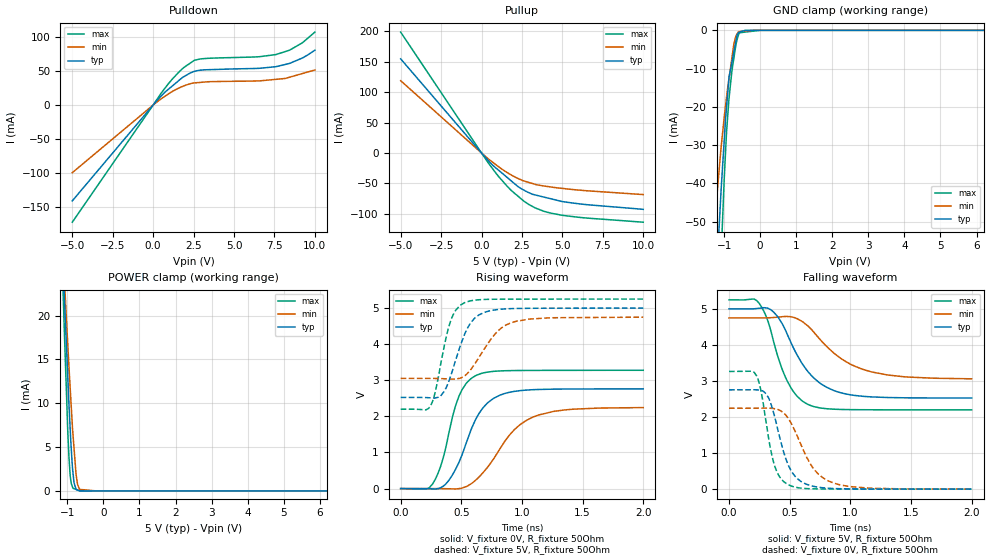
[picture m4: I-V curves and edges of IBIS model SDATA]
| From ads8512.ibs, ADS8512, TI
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|   sdata Model
[Model]   SDATA
Model_type   3-state
Polarity   Non-Inverting
Vmeas = 2.5
Vref = 2.5
Cref = 10pF
Rref = 50
|   typ   min   max
|   (nom PVT)   (Fast PVT)   (slow PVT)
|C_comp from frequency method(29MHz)
|C_comp   3.620e-12   4.211e-12   3.057e-12
|ON state : BUFFER OUTPUT TURNED HIGH
|C_comp   3.711e-12   3.139e-12   4.318e-12
|OFF state: BUFFER IN HIGH IMPEDANCE
|C_comp   3.252e-12   3.813e-12   2.654e-12
|C_comp from LC tank measurement(L=1nH)
|Resonant Frequency(Hz)   2.990e+09   3.140e+09   2.900e+09
C_comp   2.836e-12   2.572e-12   3.015e-12
|ON state : BUFFER OUTPUT TURNED HIGH
|Resonant Frequency(Hz)   2.990e+09   3.140e+09   2.900e+09
|C_comp   2.836e-12   2.572e-12   3.015e-12
|OFF state: BUFFER IN HIGH IMPEDANCE
|Resonant Frequency(Hz)   3.150e+09   3.390e+09   2.990e+09
|C_comp   2.555e-12   2.206e-12   2.836e-12
| Where nom  PVT is Nominal Process,  5V,  25C
|   Fast PVT is Strong Process,   5.25V,  -40C
|   Slow PVT is Weak Process,   4.75V,  85C
[Voltage Range]   5   4.75   5.25
|Ambient Temperature   25   85   -40
|Junction Temperature
[Temperature Range]   25   85   -40
[Pullup Reference]   5   4.75   5.25
[Pulldown Reference]   0   0   0
[Power Clamp Reference]   5   4.75   5.25
[GND Clamp Reference]   0   0   0
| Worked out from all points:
|   slope of the pulldown table from 0 to 0.75 V, typ, clamps not added: 38.6 ohm
|   slope of the pullup table from 0 to 0.75 V, typ, clamps not added: 34.9 ohm
|   GND clamp passes 1 mA (typ) near -0.63 V on its own axis
|   POWER clamp passes 1 mA (typ) near -0.82 V on its own axis
|   falling waveform, V_fixture 5V, R_fixture 50Ohm: 20-80 % time 269ps typ, 361ps min, 188ps max; typ from 5 V to 2.53 V
|   rising waveform, V_fixture 0V, R_fixture 50Ohm: 20-80 % time 217ps typ, 314ps min, 156ps max; typ from 0 V to 2.76 V
|   rising waveform, V_fixture 5V, R_fixture 50Ohm: 20-80 % time 159ps typ, 219ps min, 118ps max; typ from 2.52 V to 5 V
|   falling waveform, V_fixture 0V, R_fixture 50Ohm: 20-80 % time 146ps typ, 209ps min, 106ps max; typ from 2.76 V to 0.004 V
[Pulldown]
|   Voltage   I(typ)   I(min)   I(max)
-5V       -141.2mA   -99.65mA   -172.6mA
255mV     7.087mA    4.92mA     8.994mA
700mV     18.42mA    12.51mA    23.9mA
1.145V    27.31mA    19.44mA    37.2mA
1.906V    41.92mA    28.28mA    55.49mA
2.551V    49.63mA    32.64mA    66mA
2.94V     51.44mA    33.43mA    68.06mA
6.557V    54.15mA    35.59mA    71.22mA
7.591V    56.54mA    37.88mA    74.4mA
8.442V    61.44mA    41.08mA    80.94mA
9.229V    69.37mA    46.44mA    91.74mA
10V       80.82mA    51.68mA    107.5mA
[GND Clamp]
|   Voltage   I(typ)   I(min)   I(max)
-5V       -873.3mA   -631.6mA   -1.21A
-1.306V   -81.05mA   -54.86mA   -119.8mA
-1.176V   -58.06mA   -40.62mA   -83.69mA
-1.093V   -43.33mA   -31.5mA    -61.76mA
-1.071V   -39.84mA   -29.49mA   -56.18mA
-997.5mV  -28.82mA   -22.72mA   -38.9mA
-934.5mV  -20.28mA   -17.65mA   -27.02mA
-866.2mV  -12.47mA   -12.74mA   -17.97mA
-726.8mV  -5.5mA     -3.506mA   -7.118mA
-598.5mV  -597.9uA   -334.5uA   -1.123mA
0V        0A         0A         0A
10V       0A         0A         0A
[Pullup]
|   Voltage   I(typ)   I(min)   I(max)
-5V       154.7mA    118.9mA    198.7mA
409.5mV   -12.21mA   -9.375mA   -15.99mA
1.076V    -28.81mA   -23.13mA   -39.34mA
1.596V    -40.46mA   -32.36mA   -55.04mA
2.27V     -55.56mA   -42.15mA   -71.34mA
2.63V     -61.26mA   -46.07mA   -79.42mA
3.165V    -68.02mA   -50.33mA   -88.09mA
3.838V    -72.38mA   -54.2mA    -95.66mA
4.956V    -79.64mA   -58.13mA   -102.3mA
6.565V    -85.13mA   -62.24mA   -107.1mA
10V       -92.7mA    -68.39mA   -113.8mA
[POWER Clamp]
|   Voltage   I(typ)   I(min)   I(max)
-5V       154.8mA    142.8mA    170.1mA
-1.306V   45.1mA     42.24mA    48.1mA
-1.092V   23.02mA    24.86mA    19.22mA
-1.085V   22.3mA     24.3mA     18.38mA
-987mV    12.87mA    16.58mA    6.678mA
-955.5mV  9.842mA    14.15mA    3.833mA
-918.7mV  6.803mA    11.51mA    1.634mA
-865mV    3.014mA    7.677mA    531.2uA
-815mV    936.6uA    4.87mA     258.7uA
-755.2mV  166.1uA    1.78mA     170.5uA
-665mV    8.504uA    175.7uA    37.22uA
10V       0A         0A         0A
[Ramp]
R_load = 50
|   typ   min   max
dV/dt_r   1.65719/2.1708e-10   1.34628/3.12687e-10   1.9662/1.55353e-10
dV/dt_f   1.48295/2.67606e-10   1.01315/3.60262e-10   1.82998/1.88135e-10
[Falling Waveform]
V_fixture = 5V
V_fixture_min = 4.75V
V_fixture_max = 5.25V
R_fixture = 50Ohm
|   Time   V(typ)   V(min)   V(max)
0s        5V         4.75V      5.25V
248.1ps   5.017V     4.749V     5.157V
320.5ps   5.017V     4.753V     4.663V
369.1ps   4.907V     4.761V     4.072V
478.8ps   4.305V     4.791V     3.008V
562.1ps   3.716V     4.728V     2.576V
656.2ps   3.239V     4.508V     2.343V
859.6ps   2.743V     3.788V     2.22V
1.101ns   2.577V     3.325V     2.204V
2ns       2.528V     3.061V     2.2V
[Rising Waveform]
V_fixture = 0V
V_fixture_min = 0V
V_fixture_max = 0V
R_fixture = 50Ohm
|   Time   V(typ)   V(min)   V(max)
0s        1.441nV    1.696nV    1.282nV
265ps     -8.943mV   688.7uV    136mV
349.1ps   62.08mV    -1.828mV   830.7mV
430.5ps   399.2mV    -8.475mV   2.031V
478.5ps   711.8mV    -1.793mV   2.541V
621.9ps   1.938V     243.6mV    3.134V
768.4ps   2.504V     832.9mV    3.248V
934.4ps   2.691V     1.622V     3.269V
1.094ns   2.74V      1.985V     3.273V
2ns       2.762V     2.244V     3.277V
[Rising Waveform]
V_fixture = 5V
V_fixture_min = 4.75V
V_fixture_max = 5.25V
R_fixture = 50Ohm
|   Time   V(typ)   V(min)   V(max)
0s        2.524V     3.051V     2.198V
244.1ps   2.514V     3.052V     2.28V
281.7ps   2.507V     3.05V      2.628V
335.3ps   2.589V     3.046V     3.539V
408.6ps   3.082V     3.033V     4.609V
529.5ps   4.292V     3.128V     5.152V
643.9ps   4.807V     3.625V     5.23V
785.3ps   4.953V     4.308V     5.244V
908.4ps   4.984V     4.59V      5.246V
2ns       4.998V     4.748V     5.249V
[Falling Waveform]
V_fixture = 0V
V_fixture_min = 0V
V_fixture_max = 0V
R_fixture = 50Ohm
|   Time   V(typ)   V(min)   V(max)
0s        2.756V     2.246V     3.265V
227.4ps   2.756V     2.247V     3.144V
266ps     2.737V     2.249V     2.684V
305.9ps   2.64V      2.249V     1.856V
371.2ps   2.073V     2.235V     702.7mV
492.4ps   639.9mV    1.943V     118.7mV
575ps     261.3mV    1.379V     38.51mV
692.2ps   83.71mV    591.4mV    11.15mV
865.9ps   19.92mV    167.4mV    5.974mV
2ns       3.73mV     4.965mV    2.019mV
